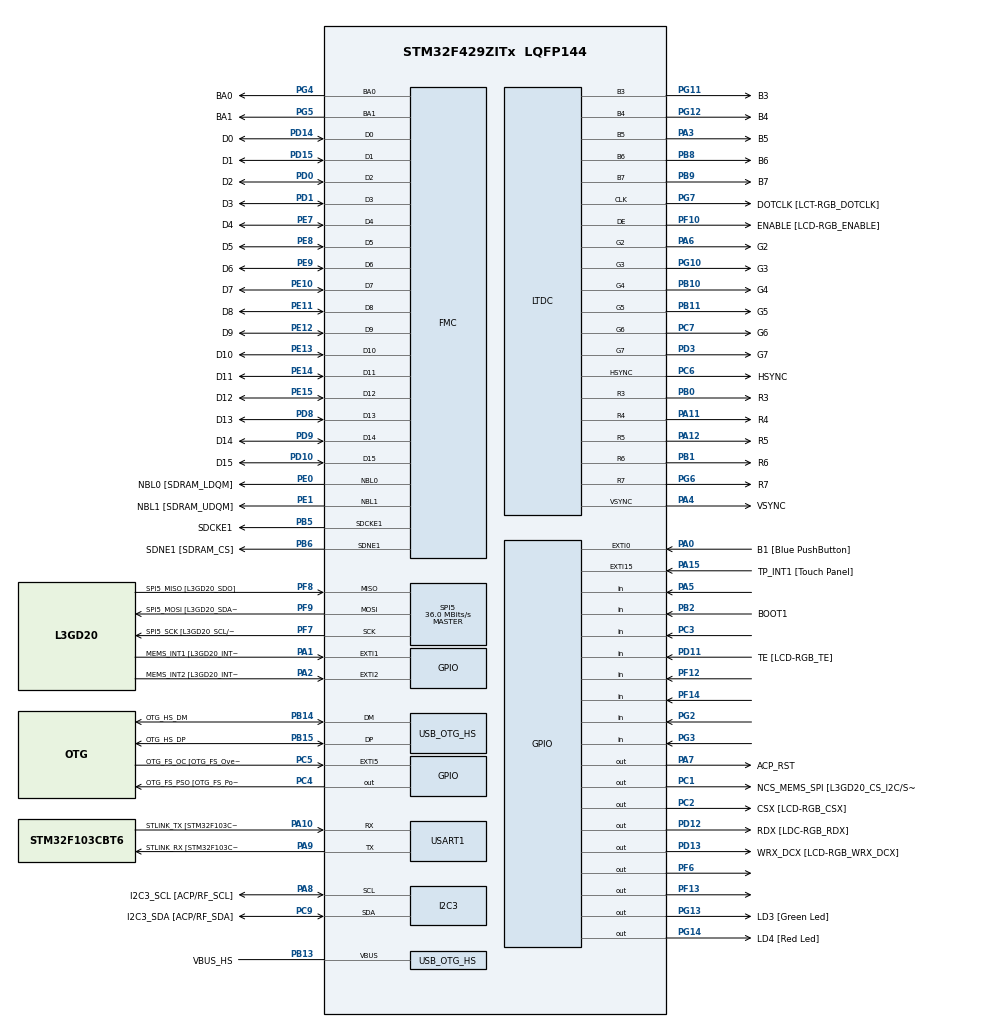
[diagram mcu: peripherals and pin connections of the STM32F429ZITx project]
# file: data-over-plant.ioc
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LTDC.ActiveH=320
LTDC.ActiveW=240
LTDC.Alpha_L0=255
LTDC.BlendingFactor1_L0=LTDC_BLENDING_FACTOR1_PAxCA
LTDC.BlendingFactor2_L0=LTDC_BLENDING_FACTOR2_PAxCA
LTDC.FBStartAdress_L0=0xD0000000
LTDC.HBP=20
LTDC.HFP=10
LTDC.HSync=10
LTDC.ImageHeight_L0=320
LTDC.ImageWidth_L0=240
LTDC.Layers=0
LTDC.PixelFormat_L0=LTDC_PIXEL_FORMAT_RGB565
LTDC.VFP=4
LTDC.VSync=2
LTDC.WindowX1_L0=240
LTDC.WindowY1_L0=320
Mcu.Family=STM32F4
Mcu.Name=STM32F429ZITx
Mcu.Package=LQFP144
NVIC.DMA2D_IRQn=true\:5\:0\:true\:false\:true\:true\:true\:true
NVIC.LTDC_IRQn=true\:5\:0\:true\:false\:true\:true\:true\:true
NVIC.OTG_HS_IRQn=true\:0\:0\:false\:false\:true\:true\:true\:true
NVIC.PriorityGroup=NVIC_PRIORITYGROUP_4
NVIC.TIM6_DAC_IRQn=true\:15\:0\:false\:false\:true\:false\:true\:true
NVIC.TimeBase=TIM6_DAC_IRQn
NVIC.TimeBaseIP=TIM6
PA0/WKUP.GPIO_Label=B1 [Blue PushButton]
PA0/WKUP.GPIO_ModeDefaultEXTI=GPIO_MODE_EVT_RISING
PA0/WKUP.GPIO_PuPd=GPIO_NOPULL
PA0/WKUP.Signal=GPXTI0
PA1.GPIO_Label=MEMS_INT1 [L3GD20_INT1]
PA1.GPIO_ModeDefaultEXTI=GPIO_MODE_EVT_RISING
PA1.GPIO_PuPd=GPIO_NOPULL
PA1.Signal=GPXTI1
PA10.GPIO_Label=STLINK_TX [STM32F103CBT6_PA2]
PA10.Mode=Asynchronous
PA10.Signal=USART1_RX
PA11.GPIO_Label=R4
PA11.GPIO_Mode=GPIO_MODE_AF_PP
PA11.GPIO_PuPd=GPIO_NOPULL
PA11.GPIO_Speed=GPIO_SPEED_FREQ_LOW
PA11.Mode=RGB565
PA11.Signal=LTDC_R4
PA12.GPIO_Label=R5
PA12.GPIO_Mode=GPIO_MODE_AF_PP
PA12.GPIO_PuPd=GPIO_NOPULL
PA12.GPIO_Speed=GPIO_SPEED_FREQ_LOW
PA12.Mode=RGB565
PA12.Signal=LTDC_R5
PA13.GPIO_Label=SWDIO
PA13.Mode=Serial_Wire
PA13.Signal=SYS_JTMS-SWDIO
PA14.GPIO_Label=SWCLK
PA14.Mode=Serial_Wire
PA14.Signal=SYS_JTCK-SWCLK
PA15.GPIO_Label=TP_INT1 [Touch Panel]
PA15.GPIO_ModeDefaultEXTI=GPIO_MODE_EVT_RISING
PA15.GPIO_PuPd=GPIO_NOPULL
PA15.Signal=GPXTI15
PA2.GPIO_Label=MEMS_INT2 [L3GD20_INT2]
PA2.GPIO_ModeDefaultEXTI=GPIO_MODE_EVT_RISING
PA2.GPIO_PuPd=GPIO_NOPULL
PA2.Signal=GPXTI2
PA3.GPIO_Label=B5
PA3.GPIO_Mode=GPIO_MODE_AF_PP
PA3.GPIO_PuPd=GPIO_NOPULL
PA3.GPIO_Speed=GPIO_SPEED_FREQ_LOW
PA3.Mode=RGB565
PA3.Signal=LTDC_B5
PA4.GPIO_Label=VSYNC
PA4.GPIO_Mode=GPIO_MODE_AF_PP
PA4.GPIO_PuPd=GPIO_NOPULL
PA4.GPIO_Speed=GPIO_SPEED_FREQ_LOW
PA4.Mode=RGB565
PA4.Signal=LTDC_VSYNC
PA5.Signal=GPIO_Input
PA6.GPIO_Label=G2
PA6.GPIO_Mode=GPIO_MODE_AF_PP
PA6.GPIO_PuPd=GPIO_NOPULL
PA6.GPIO_Speed=GPIO_SPEED_FREQ_LOW
PA6.Mode=RGB565
PA6.Signal=LTDC_G2
PA7.GPIO_Label=ACP_RST
PA7.GPIO_Mode=GPIO_MODE_OUTPUT_PP
PA7.GPIO_PuPd=GPIO_NOPULL
PA7.GPIO_Speed=GPIO_SPEED_FREQ_LOW
PA7.Signal=GPIO_Output
PA8.GPIO_Label=I2C3_SCL [ACP/RF_SCL]
PA8.GPIO_Mode=GPIO_MODE_AF_OD
PA8.GPIO_Pu=GPIO_PULLUP
PA8.GPIO_PuPd=GPIO_NOPULL
PA8.GPIO_Speed=GPIO_SPEED_FREQ_LOW
PA8.Mode=I2C
PA8.Signal=I2C3_SCL
PA9.GPIO_Label=STLINK_RX [STM32F103CBT6_PA3]
PA9.Mode=Asynchronous
PA9.Signal=USART1_TX
PB0.GPIO_Label=R3
PB0.GPIO_Mode=GPIO_MODE_AF_PP
PB0.GPIO_PuPd=GPIO_NOPULL
PB0.GPIO_Speed=GPIO_SPEED_FREQ_LOW
PB0.Mode=RGB565
PB0.Signal=LTDC_R3
PB1.GPIO_Label=R6
PB1.GPIO_Mode=GPIO_MODE_AF_PP
PB1.GPIO_PuPd=GPIO_NOPULL
PB1.GPIO_Speed=GPIO_SPEED_FREQ_LOW
PB1.Mode=RGB565
PB1.Signal=LTDC_R6
PB10.GPIO_Label=G4
PB10.GPIO_Mode=GPIO_MODE_AF_PP
PB10.GPIO_PuPd=GPIO_NOPULL
PB10.GPIO_Speed=GPIO_SPEED_FREQ_LOW
PB10.Mode=RGB565
PB10.Signal=LTDC_G4
PB11.GPIO_Label=G5
PB11.GPIO_Mode=GPIO_MODE_AF_PP
PB11.GPIO_PuPd=GPIO_NOPULL
PB11.GPIO_Speed=GPIO_SPEED_FREQ_LOW
PB11.Mode=RGB565
PB11.Signal=LTDC_G5
PB12.GPIO_Label=OTG_HS_ID
PB12.GPIO_Mode=GPIO_MODE_AF_PP
PB12.GPIO_PuPd=GPIO_NOPULL
PB12.GPIO_Speed=GPIO_SPEED_FREQ_LOW
PB12.Signal=USB_OTG_HS_ID
PB13.GPIO_Label=VBUS_HS
PB13.GPIO_Mode=GPIO_MODE_INPUT
PB13.GPIO_PuPd=GPIO_NOPULL
PB13.Mode=Activate_VBUS_FS
PB13.Signal=USB_OTG_HS_VBUS
PB14.GPIO_Label=OTG_HS_DM
PB14.GPIO_Mode=GPIO_MODE_AF_PP
PB14.GPIO_PuPd=GPIO_NOPULL
PB14.GPIO_Speed=GPIO_SPEED_FREQ_LOW
PB14.Mode=Host_FS
PB14.Signal=USB_OTG_HS_DM
PB15.GPIO_Label=OTG_HS_DP
PB15.GPIO_Mode=GPIO_MODE_AF_PP
PB15.GPIO_PuPd=GPIO_NOPULL
PB15.GPIO_Speed=GPIO_SPEED_FREQ_LOW
PB15.Mode=Host_FS
PB15.Signal=USB_OTG_HS_DP
PB2/BOOT1.GPIO_Label=BOOT1
PB2/BOOT1.GPIO_Mode=GPIO_MODE_INPUT
PB2/BOOT1.GPIO_PuPd=GPIO_NOPULL
PB2/BOOT1.Signal=GPIO_Input
PB5.GPIO_Label=SDCKE1
PB5.GPIO_Mode=GPIO_MODE_AF_PP
PB5.GPIO_PuPd=GPIO_NOPULL
PB5.GPIO_Speed=GPIO_SPEED_FREQ_VERY_HIGH
PB5.Mode=SdramChipSelect2_1
PB5.Signal=FMC_SDCKE1
PB6.GPIO_Label=SDNE1 [SDRAM_CS]
PB6.GPIO_Mode=GPIO_MODE_AF_PP
PB6.GPIO_PuPd=GPIO_NOPULL
PB6.GPIO_Speed=GPIO_SPEED_FREQ_VERY_HIGH
PB6.Mode=SdramChipSelect2_1
PB6.Signal=FMC_SDNE1
PB8.GPIO_Label=B6
PB8.GPIO_Mode=GPIO_MODE_AF_PP
PB8.GPIO_PuPd=GPIO_NOPULL
PB8.GPIO_Speed=GPIO_SPEED_FREQ_LOW
PB8.Mode=RGB565
PB8.Signal=LTDC_B6
PB9.GPIO_Label=B7
PB9.GPIO_Mode=GPIO_MODE_AF_PP
PB9.GPIO_PuPd=GPIO_NOPULL
PB9.GPIO_Speed=GPIO_SPEED_FREQ_LOW
PB9.Mode=RGB565
PB9.Signal=LTDC_B7
PC0.GPIO_Label=SDNWE
PC0.GPIO_Mode=GPIO_MODE_AF_PP
PC0.GPIO_PuPd=GPIO_NOPULL
PC0.GPIO_Speed=GPIO_SPEED_FREQ_VERY_HIGH
PC0.Signal=FMC_SDNWE
PC1.GPIO_Label=NCS_MEMS_SPI [L3GD20_CS_I2C/SPI]
PC1.GPIO_Mode=GPIO_MODE_OUTPUT_PP
PC1.GPIO_PuPd=GPIO_NOPULL
PC1.GPIO_Speed=GPIO_SPEED_FREQ_LOW
PC1.Signal=GPIO_Output
PC10.GPIO_Label=R2
PC10.GPIO_Mode=GPIO_MODE_AF_PP
PC10.GPIO_PuPd=GPIO_NOPULL
PC10.GPIO_Speed=GPIO_SPEED_FREQ_LOW
PC10.Signal=LTDC_R2
PC14/OSC32_IN.GPIO_Label=PC14-OSC32_IN
PC14/OSC32_IN.Signal=RCC_OSC32_IN
PC15/OSC32_OUT.GPIO_Label=PC15-OSC32_OUT
PC15/OSC32_OUT.Signal=RCC_OSC32_OUT
PC2.GPIO_Label=CSX [LCD-RGB_CSX]
PC2.GPIO_Mode=GPIO_MODE_OUTPUT_PP
PC2.GPIO_PuPd=GPIO_NOPULL
PC2.GPIO_Speed=GPIO_SPEED_FREQ_LOW
PC2.Signal=GPIO_Output
PC3.Signal=GPIO_Input
PC4.GPIO_Label=OTG_FS_PSO [OTG_FS_PowerSwitchOn]
PC4.GPIO_Mode=GPIO_MODE_OUTPUT_PP
PC4.GPIO_PuPd=GPIO_NOPULL
PC4.GPIO_Speed=GPIO_SPEED_FREQ_LOW
PC4.Signal=GPIO_Output
PC5.GPIO_Label=OTG_FS_OC [OTG_FS_OverCurrent]
PC5.GPIO_ModeDefaultEXTI=GPIO_MODE_EVT_RISING
PC5.Signal=GPXTI5
PC6.GPIO_Label=HSYNC
PC6.GPIO_Mode=GPIO_MODE_AF_PP
PC6.GPIO_PuPd=GPIO_NOPULL
PC6.GPIO_Speed=GPIO_SPEED_FREQ_LOW
PC6.Mode=RGB565
PC6.Signal=LTDC_HSYNC
PC7.GPIO_Label=G6
PC7.GPIO_Mode=GPIO_MODE_AF_PP
PC7.GPIO_PuPd=GPIO_NOPULL
PC7.GPIO_Speed=GPIO_SPEED_FREQ_LOW
PC7.Mode=RGB565
PC7.Signal=LTDC_G6
PC9.GPIO_Label=I2C3_SDA [ACP/RF_SDA]
PC9.GPIO_Mode=GPIO_MODE_AF_OD
PC9.GPIO_Pu=GPIO_PULLUP
PC9.GPIO_PuPd=GPIO_NOPULL
PC9.GPIO_Speed=GPIO_SPEED_FREQ_LOW
PC9.Mode=I2C
PC9.Signal=I2C3_SDA
PD0.GPIO_Label=D2
PD0.GPIO_Mode=GPIO_MODE_AF_PP
PD0.GPIO_PuPd=GPIO_NOPULL
PD0.GPIO_Speed=GPIO_SPEED_FREQ_VERY_HIGH
PD0.Signal=FMC_D2_DA2
PD1.GPIO_Label=D3
PD1.GPIO_Mode=GPIO_MODE_AF_PP
PD1.GPIO_PuPd=GPIO_NOPULL
PD1.GPIO_Speed=GPIO_SPEED_FREQ_VERY_HIGH
PD1.Signal=FMC_D3_DA3
PD10.GPIO_Label=D15
PD10.GPIO_Mode=GPIO_MODE_AF_PP
PD10.GPIO_PuPd=GPIO_NOPULL
PD10.GPIO_Speed=GPIO_SPEED_FREQ_VERY_HIGH
PD10.Signal=FMC_D15_DA15
PD11.GPIO_Label=TE [LCD-RGB_TE]
PD11.GPIO_Mode=GPIO_MODE_INPUT
PD11.GPIO_PuPd=GPIO_NOPULL
PD11.Signal=GPIO_Input
PD12.GPIO_Label=RDX [LDC-RGB_RDX]
PD12.GPIO_Mode=GPIO_MODE_OUTPUT_PP
PD12.GPIO_PuPd=GPIO_NOPULL
PD12.GPIO_Speed=GPIO_SPEED_FREQ_LOW
PD12.Signal=GPIO_Output
PD13.GPIO_Label=WRX_DCX [LCD-RGB_WRX_DCX]
PD13.GPIO_Mode=GPIO_MODE_OUTPUT_PP
PD13.GPIO_PuPd=GPIO_NOPULL
PD13.GPIO_Speed=GPIO_SPEED_FREQ_LOW
PD13.Signal=GPIO_Output
PD14.GPIO_Label=D0
PD14.GPIO_Mode=GPIO_MODE_AF_PP
PD14.GPIO_PuPd=GPIO_NOPULL
PD14.GPIO_Speed=GPIO_SPEED_FREQ_VERY_HIGH
PD14.Signal=FMC_D0_DA0
PD15.GPIO_Label=D1
PD15.GPIO_Mode=GPIO_MODE_AF_PP
PD15.GPIO_PuPd=GPIO_NOPULL
PD15.GPIO_Speed=GPIO_SPEED_FREQ_VERY_HIGH
PD15.Signal=FMC_D1_DA1
PD3.GPIO_Label=G7
PD3.GPIO_Mode=GPIO_MODE_AF_PP
PD3.GPIO_PuPd=GPIO_NOPULL
PD3.GPIO_Speed=GPIO_SPEED_FREQ_LOW
PD3.Mode=RGB565
PD3.Signal=LTDC_G7
PD6.GPIO_Label=B2
PD6.GPIO_Mode=GPIO_MODE_AF_PP
PD6.GPIO_PuPd=GPIO_NOPULL
PD6.GPIO_Speed=GPIO_SPEED_FREQ_LOW
PD6.Signal=LTDC_B2
PD8.GPIO_Label=D13
PD8.GPIO_Mode=GPIO_MODE_AF_PP
PD8.GPIO_PuPd=GPIO_NOPULL
PD8.GPIO_Speed=GPIO_SPEED_FREQ_VERY_HIGH
PD8.Signal=FMC_D13_DA13
PD9.GPIO_Label=D14
PD9.GPIO_Mode=GPIO_MODE_AF_PP
PD9.GPIO_PuPd=GPIO_NOPULL
PD9.GPIO_Speed=GPIO_SPEED_FREQ_VERY_HIGH
PD9.Signal=FMC_D14_DA14
PE0.GPIO_Label=NBL0 [SDRAM_LDQM]
PE0.GPIO_Mode=GPIO_MODE_AF_PP
PE0.GPIO_PuPd=GPIO_NOPULL
PE0.GPIO_Speed=GPIO_SPEED_FREQ_VERY_HIGH
PE0.Signal=FMC_NBL0
PE1.GPIO_Label=NBL1 [SDRAM_UDQM]
PE1.GPIO_Mode=GPIO_MODE_AF_PP
PE1.GPIO_PuPd=GPIO_NOPULL
PE1.GPIO_Speed=GPIO_SPEED_FREQ_VERY_HIGH
PE1.Signal=FMC_NBL1
PE10.GPIO_Label=D7
PE10.GPIO_Mode=GPIO_MODE_AF_PP
PE10.GPIO_PuPd=GPIO_NOPULL
PE10.GPIO_Speed=GPIO_SPEED_FREQ_VERY_HIGH
PE10.Signal=FMC_D7_DA7
PE11.GPIO_Label=D8
PE11.GPIO_Mode=GPIO_MODE_AF_PP
PE11.GPIO_PuPd=GPIO_NOPULL
PE11.GPIO_Speed=GPIO_SPEED_FREQ_VERY_HIGH
PE11.Signal=FMC_D8_DA8
PE12.GPIO_Label=D9
PE12.GPIO_Mode=GPIO_MODE_AF_PP
PE12.GPIO_PuPd=GPIO_NOPULL
PE12.GPIO_Speed=GPIO_SPEED_FREQ_VERY_HIGH
PE12.Signal=FMC_D9_DA9
PE13.GPIO_Label=D10
PE13.GPIO_Mode=GPIO_MODE_AF_PP
PE13.GPIO_PuPd=GPIO_NOPULL
PE13.GPIO_Speed=GPIO_SPEED_FREQ_VERY_HIGH
PE13.Signal=FMC_D10_DA10
PE14.GPIO_Label=D11
PE14.GPIO_Mode=GPIO_MODE_AF_PP
PE14.GPIO_PuPd=GPIO_NOPULL
PE14.GPIO_Speed=GPIO_SPEED_FREQ_VERY_HIGH
PE14.Signal=FMC_D11_DA11
PE15.GPIO_Label=D12
PE15.GPIO_Mode=GPIO_MODE_AF_PP
PE15.GPIO_PuPd=GPIO_NOPULL
PE15.GPIO_Speed=GPIO_SPEED_FREQ_VERY_HIGH
PE15.Signal=FMC_D12_DA12
PE7.GPIO_Label=D4
PE7.GPIO_Mode=GPIO_MODE_AF_PP
PE7.GPIO_PuPd=GPIO_NOPULL
PE7.GPIO_Speed=GPIO_SPEED_FREQ_VERY_HIGH
PE7.Signal=FMC_D4_DA4
PE8.GPIO_Label=D5
PE8.GPIO_Mode=GPIO_MODE_AF_PP
PE8.GPIO_PuPd=GPIO_NOPULL
PE8.GPIO_Speed=GPIO_SPEED_FREQ_VERY_HIGH
PE8.Signal=FMC_D5_DA5
PE9.GPIO_Label=D6
PE9.GPIO_Mode=GPIO_MODE_AF_PP
PE9.GPIO_PuPd=GPIO_NOPULL
PE9.GPIO_Speed=GPIO_SPEED_FREQ_VERY_HIGH
PE9.Signal=FMC_D6_DA6
PF0.GPIO_Label=A0
PF0.GPIO_Mode=GPIO_MODE_AF_PP
PF0.GPIO_PuPd=GPIO_NOPULL
PF0.GPIO_Speed=GPIO_SPEED_FREQ_VERY_HIGH
PF0.Signal=FMC_A0
PF1.GPIO_Label=A1
PF1.GPIO_Mode=GPIO_MODE_AF_PP
PF1.GPIO_PuPd=GPIO_NOPULL
PF1.GPIO_Speed=GPIO_SPEED_FREQ_VERY_HIGH
PF1.Signal=FMC_A1
PF10.GPIO_Label=ENABLE [LCD-RGB_ENABLE]
PF10.GPIO_Mode=GPIO_MODE_AF_PP
PF10.GPIO_PuPd=GPIO_NOPULL
PF10.GPIO_Speed=GPIO_SPEED_FREQ_LOW
PF10.Mode=RGB565
PF10.Signal=LTDC_DE
PF11.GPIO_Label=SDNRAS
PF11.GPIO_Mode=GPIO_MODE_AF_PP
PF11.GPIO_PuPd=GPIO_NOPULL
PF11.GPIO_Speed=GPIO_SPEED_FREQ_VERY_HIGH
PF11.Signal=FMC_SDNRAS
PF12.Signal=GPIO_Input
PF13.Signal=GPIO_Output
PF14.Signal=GPIO_Input
PF15.GPIO_Label=A9
PF15.GPIO_Mode=GPIO_MODE_AF_PP
PF15.GPIO_PuPd=GPIO_NOPULL
PF15.GPIO_Speed=GPIO_SPEED_FREQ_VERY_HIGH
PF15.Signal=FMC_A9
PF2.GPIO_Label=A2
PF2.GPIO_Mode=GPIO_MODE_AF_PP
PF2.GPIO_PuPd=GPIO_NOPULL
PF2.GPIO_Speed=GPIO_SPEED_FREQ_VERY_HIGH
PF2.Signal=FMC_A2
PF3.GPIO_Label=A3
PF3.GPIO_Mode=GPIO_MODE_AF_PP
PF3.GPIO_PuPd=GPIO_NOPULL
PF3.GPIO_Speed=GPIO_SPEED_FREQ_VERY_HIGH
PF3.Signal=FMC_A3
PF4.GPIO_Label=A4
PF4.GPIO_Mode=GPIO_MODE_AF_PP
PF4.GPIO_PuPd=GPIO_NOPULL
PF4.GPIO_Speed=GPIO_SPEED_FREQ_VERY_HIGH
PF4.Signal=FMC_A4
PF5.GPIO_Label=A5
PF5.GPIO_Mode=GPIO_MODE_AF_PP
PF5.GPIO_PuPd=GPIO_NOPULL
PF5.GPIO_Speed=GPIO_SPEED_FREQ_VERY_HIGH
PF5.Signal=FMC_A5
PF6.Signal=GPIO_Output
PF7.GPIO_Label=SPI5_SCK [L3GD20_SCL/SPC]
PF7.GPIO_Mode=GPIO_MODE_AF_PP
PF7.GPIO_PuPd=GPIO_NOPULL
PF7.GPIO_Speed=GPIO_SPEED_FREQ_LOW
PF7.Mode=Full_Duplex_Master
PF7.Signal=SPI5_SCK
PF8.GPIO_Label=SPI5_MISO [L3GD20_SDO]
PF8.GPIO_Mode=GPIO_MODE_AF_PP
PF8.GPIO_PuPd=GPIO_NOPULL
PF8.GPIO_Speed=GPIO_SPEED_FREQ_LOW
PF8.Mode=Full_Duplex_Master
PF8.Signal=SPI5_MISO
PF9.GPIO_Label=SPI5_MOSI [L3GD20_SDA/SDI/SDO]
PF9.GPIO_Mode=GPIO_MODE_AF_PP
PF9.GPIO_PuPd=GPIO_NOPULL
PF9.GPIO_Speed=GPIO_SPEED_FREQ_LOW
PF9.Mode=Full_Duplex_Master
PF9.Signal=SPI5_MOSI
PG0.GPIO_Label=A10
PG0.GPIO_Mode=GPIO_MODE_AF_PP
PG0.GPIO_PuPd=GPIO_NOPULL
PG0.GPIO_Speed=GPIO_SPEED_FREQ_VERY_HIGH
PG0.Signal=FMC_A10
PG1.GPIO_Label=A11
PG1.GPIO_Mode=GPIO_MODE_AF_PP
PG1.GPIO_PuPd=GPIO_NOPULL
PG1.GPIO_Speed=GPIO_SPEED_FREQ_VERY_HIGH
PG1.Signal=FMC_A11
PG10.GPIO_Label=G3
PG10.GPIO_Mode=GPIO_MODE_AF_PP
PG10.GPIO_PuPd=GPIO_NOPULL
PG10.GPIO_Speed=GPIO_SPEED_FREQ_LOW
PG10.Mode=RGB565
PG10.Signal=LTDC_G3
PG11.GPIO_Label=B3
PG11.GPIO_Mode=GPIO_MODE_AF_PP
PG11.GPIO_PuPd=GPIO_NOPULL
PG11.GPIO_Speed=GPIO_SPEED_FREQ_LOW
PG11.Mode=RGB565
PG11.Signal=LTDC_B3
PG12.GPIO_Label=B4
PG12.GPIO_Mode=GPIO_MODE_AF_PP
PG12.GPIO_PuPd=GPIO_NOPULL
PG12.GPIO_Speed=GPIO_SPEED_FREQ_LOW
PG12.Mode=RGB565
PG12.Signal=LTDC_B4
PG13.GPIO_Label=LD3 [Green Led]
PG13.GPIO_Mode=GPIO_MODE_OUTPUT_PP
PG13.GPIO_PuPd=GPIO_NOPULL
PG13.GPIO_Speed=GPIO_SPEED_FREQ_LOW
PG13.Signal=GPIO_Output
PG14.GPIO_Label=LD4 [Red Led]
PG14.GPIO_Mode=GPIO_MODE_OUTPUT_PP
PG14.GPIO_PuPd=GPIO_NOPULL
PG14.GPIO_Speed=GPIO_SPEED_FREQ_LOW
PG14.Signal=GPIO_Output
PG15.GPIO_Label=SDNCAS
PG15.GPIO_Mode=GPIO_MODE_AF_PP
PG15.GPIO_PuPd=GPIO_NOPULL
PG15.GPIO_Speed=GPIO_SPEED_FREQ_VERY_HIGH
PG15.Signal=FMC_SDNCAS
PG2.Signal=GPIO_Input
PG3.Signal=GPIO_Input
PG4.GPIO_Label=BA0
PG4.GPIO_Mode=GPIO_MODE_AF_PP
PG4.GPIO_PuPd=GPIO_NOPULL
PG4.GPIO_Speed=GPIO_SPEED_FREQ_VERY_HIGH
PG4.Signal=FMC_A14_BA0
PG5.GPIO_Label=BA1
PG5.GPIO_Mode=GPIO_MODE_AF_PP
PG5.GPIO_PuPd=GPIO_NOPULL
PG5.GPIO_Speed=GPIO_SPEED_FREQ_VERY_HIGH
PG5.Signal=FMC_A15_BA1
PG6.GPIO_Label=R7
PG6.GPIO_Mode=GPIO_MODE_AF_PP
PG6.GPIO_PuPd=GPIO_NOPULL
PG6.GPIO_Speed=GPIO_SPEED_FREQ_LOW
PG6.Mode=RGB565
PG6.Signal=LTDC_R7
PG7.GPIO_Label=DOTCLK [LCT-RGB_DOTCLK]
PG7.GPIO_Mode=GPIO_MODE_AF_PP
PG7.GPIO_PuPd=GPIO_NOPULL
PG7.GPIO_Speed=GPIO_SPEED_FREQ_LOW
PG7.Mode=RGB565
PG7.Signal=LTDC_CLK
PG8.GPIO_Label=SDCLK
PG8.GPIO_Mode=GPIO_MODE_AF_PP
PG8.GPIO_PuPd=GPIO_NOPULL
PG8.GPIO_Speed=GPIO_SPEED_FREQ_VERY_HIGH
PG8.Signal=FMC_SDCLK
PH0/OSC_IN.GPIO_Label=PH0-OSC_IN
PH0/OSC_IN.Mode=HSE-External-Oscillator
PH0/OSC_IN.Signal=RCC_OSC_IN
PH1/OSC_OUT.GPIO_Label=PH1-OSC_OUT
PH1/OSC_OUT.Mode=HSE-External-Oscillator
PH1/OSC_OUT.Signal=RCC_OSC_OUT
ProjectManager.HeapSize=0x200
ProjectManager.StackSize=0x400
ProjectManager.TargetToolchain=STM32CubeIDE
RCC.48MHZClocksFreq_Value=48000000
RCC.AHBFreq_Value=72000000
RCC.APB1CLKDivider=RCC_HCLK_DIV2
RCC.APB1Freq_Value=36000000
RCC.APB1TimFreq_Value=72000000
RCC.APB2Freq_Value=72000000
RCC.APB2TimFreq_Value=72000000
RCC.CortexFreq_Value=72000000
RCC.HCLKFreq_Value=72000000
RCC.HSE_VALUE=8000000
RCC.HSI_VALUE=16000000
RCC.LSE_VALUE=32768
RCC.PLLM=4
RCC.PLLN=72
RCC.PLLQ=3
RCC.PLLSAIN=50
RCC.SYSCLKFreq_VALUE=72000000
RCC.SYSCLKSource=RCC_SYSCLKSOURCE_PLLCLK
RCC.VCOOutputFreq_Value=144000000
SH.FMC_A0.0=FMC_A0
SH.FMC_A1.0=FMC_A1
SH.FMC_A10.0=FMC_A10
SH.FMC_A11.0=FMC_A11
SH.FMC_A14_BA0.0=FMC_BA0,FourSdramBanks1
SH.FMC_A15_BA1.0=FMC_BA1,FourSdramBanks1
SH.FMC_A2.0=FMC_A2
SH.FMC_A3.0=FMC_A3
SH.FMC_A4.0=FMC_A4
SH.FMC_A5.0=FMC_A5
SH.FMC_A9.0=FMC_A9
SH.FMC_D0_DA0.0=FMC_D0,sd-16b-d1
SH.FMC_D10_DA10.0=FMC_D10,sd-16b-d1
SH.FMC_D11_DA11.0=FMC_D11,sd-16b-d1
SH.FMC_D12_DA12.0=FMC_D12,sd-16b-d1
SH.FMC_D13_DA13.0=FMC_D13,sd-16b-d1
SH.FMC_D14_DA14.0=FMC_D14,sd-16b-d1
SH.FMC_D15_DA15.0=FMC_D15,sd-16b-d1
SH.FMC_D1_DA1.0=FMC_D1,sd-16b-d1
SH.FMC_D2_DA2.0=FMC_D2,sd-16b-d1
SH.FMC_D3_DA3.0=FMC_D3,sd-16b-d1
SH.FMC_D4_DA4.0=FMC_D4,sd-16b-d1
SH.FMC_D5_DA5.0=FMC_D5,sd-16b-d1
SH.FMC_D6_DA6.0=FMC_D6,sd-16b-d1
SH.FMC_D7_DA7.0=FMC_D7,sd-16b-d1
SH.FMC_D8_DA8.0=FMC_D8,sd-16b-d1
SH.FMC_D9_DA9.0=FMC_D9,sd-16b-d1
SH.FMC_NBL0.0=FMC_NBL0,Sd2ByteEnable1
SH.FMC_NBL1.0=FMC_NBL1,Sd2ByteEnable1
SH.FMC_SDCLK.0=FMC_SDCLK
SH.FMC_SDNCAS.0=FMC_SDNCAS
SH.FMC_SDNRAS.0=FMC_SDNRAS
SH.FMC_SDNWE.0=FMC_SDNWE
SPI5.CLKPolarity=SPI_POLARITY_LOW
SPI5.CalculateBaudRate=36.0 MBits/s
SPI5.Direction=SPI_DIRECTION_2LINES
SPI5.Mode=SPI_MODE_MASTER
SPI5.VirtualType=VM_MASTER
USART1.VirtualMode=VM_ASYNC
USB_OTG_HS.VirtualMode-Host_FS=Host_FS
VP_CRC_VS_CRC.Mode=CRC_Activate
VP_DMA2D_VS_DMA2D.Mode=DMA2D_Activate
VP_SYS_VS_tim6.Mode=TIM6
VP_TIM1_VS_ClockSourceINT.Mode=Internal
board=STM32F429I-DISC1

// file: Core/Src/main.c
/* USER CODE BEGIN Header */
/**
  ******************************************************************************
  * @file           : main.c
  * @brief          : Main program body
  ******************************************************************************
  * @attention
  *
  * Copyright (c) 2025 STMicroelectronics.
  * All rights reserved.
  *
  * This software is licensed under terms that can be found in the LICENSE file
  * in the root directory of this software component.
  * If no LICENSE file comes with this software, it is provided AS-IS.
  *
  ******************************************************************************
  */
/* USER CODE END Header */
#include "main.h"

/* USER CODE BEGIN Includes */
#include "../../../Drivers/BSP/STM32F429I-Discovery/stm32f429i_discovery.h"
#include "../../../Drivers/BSP/STM32F429I-Discovery/stm32f429i_discovery_lcd.h"
/* USER CODE END Includes */

/* USER CODE BEGIN PD */
//#define TRANSMITTER
//#define RECEIVER
#define LORA_NSS_GPIO_Port GPIOF
#define LORA_NSS_Pin       GPIO_PIN_6
#define LORA_RST_GPIO_Port GPIOF
#define LORA_RST_Pin       GPIO_PIN_13
#define LORA_DIO3 PC3
#define LORA_DIO5 PA5
#define LORA_DIO4 PG2
#define LORA_DIO1 PG3

#define LCD_FRAME_BUFFER_LAYER0                  (LCD_FRAME_BUFFER+0x130000)
#define LCD_FRAME_BUFFER_LAYER1                  LCD_FRAME_BUFFER
#define CONVERTED_FRAME_BUFFER                   (LCD_FRAME_BUFFER+0x260000)
//#define RECEIVER
/* USER CODE END PD */

CRC_HandleTypeDef hcrc;

DMA2D_HandleTypeDef hdma2d;

I2C_HandleTypeDef hi2c3;

LTDC_HandleTypeDef hltdc;

SPI_HandleTypeDef hspi5;

TIM_HandleTypeDef htim1;

UART_HandleTypeDef huart1;

HCD_HandleTypeDef hhcd_USB_OTG_HS;

SDRAM_HandleTypeDef hsdram1;

/* USER CODE BEGIN PV */
uint8_t TX_Buffer [] = "EDOUARD" ;
uint8_t RX_Buffer [1] ; // DATA to receive
/* USER CODE END PV */

void SystemClock_Config(void);
static void MX_GPIO_Init(void);
static void MX_CRC_Init(void);
static void MX_DMA2D_Init(void);
static void MX_I2C3_Init(void);
static void MX_LTDC_Init(void);
static void MX_SPI5_Init(void);
static void MX_TIM1_Init(void);
static void MX_USART1_UART_Init(void);
static void MX_USB_OTG_HS_HCD_Init(void);
static void MX_FMC_Init(void);

/* USER CODE BEGIN 0 */
typedef enum {
	false,
	true
} bool;

void serial_print(char* str)
{
	HAL_UART_Transmit(&huart1, (uint8_t *)str, strlen(str), HAL_MAX_DELAY);
}

void write_register(uint8_t addr, uint8_t value)
{
    uint8_t data[2];
    data[0] = addr | 0x80; // bit 7 à 1 pour écriture
    data[1] = value;

    HAL_GPIO_WritePin(LORA_NSS_GPIO_Port, LORA_NSS_Pin, GPIO_PIN_RESET); // NSS low
    HAL_SPI_Transmit(&hspi5, data, 2, HAL_MAX_DELAY);
    HAL_GPIO_WritePin(LORA_NSS_GPIO_Port, LORA_NSS_Pin, GPIO_PIN_SET);   // NSS high
}

uint8_t read_register(uint8_t addr)
{
    uint8_t value = 0;
    uint8_t reg_addr = addr & 0x7F; // bit 7 à 0 pour lecture (mask pour s'assurer que le bit 7 est à 0)

    HAL_GPIO_WritePin(LORA_NSS_GPIO_Port, LORA_NSS_Pin, GPIO_PIN_RESET); // NSS low
    HAL_SPI_Transmit(&hspi5, &reg_addr, 1, HAL_MAX_DELAY); // Envoyer l'adresse du registre
    HAL_SPI_Receive(&hspi5, &value, 1, HAL_MAX_DELAY);     // Lire la valeur du registre
    HAL_GPIO_WritePin(LORA_NSS_GPIO_Port, LORA_NSS_Pin, GPIO_PIN_SET);   // NSS high

    return value;
}

void init_lora_transmitter(void)
{
	// Mettre en veille (obligatoire avant les changements de mode)
	write_register(0x01, 0x80); // Sleep mode + LoRa

	// Choisir fréquence (ici pour 868 MHz)
	write_register(0x06, 0xD9); // RegFrfMsb = 868 MHz
	write_register(0x07, 0x06);
	write_register(0x08, 0x66);

	// Puissance d’émission (PA_BOOST, 17 dBm)
	//write_register(0x09, 0x8F); // RegPaConfig
	write_register(0x09, 0x80); // RegPaConfig: PA_SELECT=1 (PA_BOOST), OutputPower=0 (minimum)

	// Paramètres LoRa (BW=125 kHz, CR=4/5, SF=7)
	write_register(0x1D, 0x72); // RegModemConfig1: BW=125kHz, CR=4/5, explicit header
	write_register(0x1E, 0x74); // RegModemConfig2: SF=7, CRC On
	write_register(0x26, 0x04); // RegModemConfig3: LowDataRateOptimize=OFF

	// Configuration de la FIFO
	write_register(0x0E, 0x80); // RegFifoTxBaseAddr
	write_register(0x0D, 0x80); // RegFifoAddrPtr
	unsigned char size = 7;
	write_register(0x22, size); // RegPayloadLength (taille du message)

	// Écriture des données dans le FIFO
	for (int i = 0; i < size; i++) {
	  write_register(0x00, TX_Buffer[i]); // RegFifo
	}

	// Passage en mode émetteur
	write_register(0x01, 0x83); // TX mode + LoRa
}

void init_lora(void)
{
#ifdef TRANSMITTER
	init_lora_transmitter();
#endif
#ifdef RECEIVER
	init_lora_receiver();
#endif
}

void lora_reset(void)
{
    HAL_GPIO_WritePin(LORA_RST_GPIO_Port, LORA_RST_Pin, GPIO_PIN_RESET);
    HAL_Delay(10); // maintenir RESET à 0 pendant 10ms
    HAL_GPIO_WritePin(LORA_RST_GPIO_Port, LORA_RST_Pin, GPIO_PIN_SET);
    HAL_Delay(10); // attendre encore un peu après le relâchement
}

uint8_t lora_version(void)
{
	uint8_t version = read_register(0x42);

	char buf[32];
	snprintf(buf, sizeof(buf), "RegVersion = 0x%02X\r\n", version);
	serial_print(buf);

	if (version == 0x12) {
		serial_print("RFM95 détecté\r\n");
	} else {
		serial_print("Erreur RFM95 !\r\n");
	}

	return version;
}

uint8_t lora_status(void)
{
    return read_register(0x12); // RegIrqFlags
}

void lora_clear_irq(void)
{
    write_register(0x12, 0xFF); // Effacer tous les drapeaux d'interruption
}

char lora_is_tx_done(void)
{
    return (lora_status() & 0x08) != 0; // Vérifie le drapeau TxDone
}

void send_lora_packet(const uint8_t* data, uint8_t size)
{
    // Mettre en mode veille
    write_register(0x01, 0x81);  // Standby mode + LoRa

    // Configurer le pointeur FIFO pour l'écriture
    write_register(0x0D, 0x80);  // RegFifoAddrPtr

    // Écrire les données dans la FIFO
    for (int i = 0; i < size; i++) {
        write_register(0x00, data[i]);  // RegFifo
    }

    // Définir la taille des données
    write_register(0x22, size);  // RegPayloadLength

    // Démarrer la transmission
    write_register(0x01, 0x83);  // TX mode + LoRa
}

// Structure pour stocker les informations de paquet reçu
typedef struct {
    uint8_t buffer[256];  // Buffer pour stocker les données reçues
    uint8_t size;         // Taille des données reçues
    int8_t rssi;          // Force du signal
    float snr;            // Rapport signal/bruit
} LoRaPacket_t;

// Fonction pour initialiser le mode récepteur
void init_lora_receiver(void)
{
    // Mettre en veille (obligatoire avant les changements de mode)
    write_register(0x01, 0x80); // Sleep mode + LoRa

    // Choisir fréquence (ici pour 868 MHz - même fréquence que l'émetteur)
    write_register(0x06, 0xD9); // RegFrfMsb = 868 MHz
    write_register(0x07, 0x06);
    write_register(0x08, 0x66);

    // Paramètres LoRa (BW=125 kHz, CR=4/5, SF=7) - comme l'émetteur
    write_register(0x1D, 0x72); // RegModemConfig1: BW=125kHz, CR=4/5, explicit header
    write_register(0x1E, 0x74); // RegModemConfig2: SF=7, CRC On
    write_register(0x26, 0x04); // RegModemConfig3: LowDataRateOptimize=OFF

    // Optimisation pour la réception
    write_register(0x0F, 0x00); // RegFifoRxBaseAddr - adresse de base pour le buffer de réception

    // Configurer LNA (Low Noise Amplifier) pour la réception
    write_register(0x0C, 0x23); // RegLna: gain élevé, boost On

    // Configurer la détection de préambule
    write_register(0x1F, 0x08); // RegPreambleDetect: 1 octet de préambule requis

    // Régler le seuil de détection pour optimiser la sensibilité
    write_register(0x20, 0x00); // RegDetectionThreshold: valeur par défaut

    // Effacer tous les drapeaux d'interruption
    write_register(0x12, 0xFF);

    // Activer les interruptions RxDone et PayloadCrcError
    write_register(0x11, 0x00); // RegIrqFlags: désactiver toutes les interruptions

    // Passer en mode réception continue
    write_register(0x01, 0x85); // RX continuous mode + LoRa

    serial_print("Module LoRa initialisé en mode réception\r\n");
}

// Vérifier si un paquet est disponible
bool lora_is_packet_available(void)
{
    uint8_t irq_flags = read_register(0x12); // RegIrqFlags
    return (irq_flags & 0x40) != 0; // RxDone flag
}

// Vérifier si la réception contient une erreur CRC
bool lora_has_crc_error(void)
{
    uint8_t irq_flags = read_register(0x12); // RegIrqFlags
    return (irq_flags & 0x20) != 0; // PayloadCrcError flag
}

// Lire un paquet complet avec informations supplémentaires
LoRaPacket_t lora_receive_packet(void)
{
    LoRaPacket_t packet = {0};

    // Vérifier si un paquet est disponible et pas d'erreur CRC
    if (lora_is_packet_available() && !lora_has_crc_error()) {
        // Récupérer les informations de qualité du signal
        packet.rssi = -137 + read_register(0x1A); // RegRssiValue (en dBm)

        // Convertir la valeur SNR lue (complément à 2 sur 8 bits)
        int8_t raw_snr = (int8_t)read_register(0x19); // RegPktSnrValue
        packet.snr = raw_snr * 0.25f; // Convertir en dB

        // Récupérer la taille du paquet
        packet.size = read_register(0x13); // RegRxNbBytes

        // Lire l'adresse du dernier octet dans la FIFO
        uint8_t current_addr = read_register(0x10); // RegFifoRxCurrentAddr

        // Positionner le pointeur de FIFO à l'adresse du début de la réception
        write_register(0x0D, current_addr); // RegFifoAddrPtr

        // Lire les données
        for (uint8_t i = 0; i < packet.size && i < sizeof(packet.buffer); i++) {
            packet.buffer[i] = read_register(0x00); // RegFifo
        }

        // Afficher les informations de réception
        char buf[128];
        snprintf(buf, sizeof(buf), "Paquet reçu (%d octets), RSSI: %d dBm, SNR: %.2f dB\r\n", packet.size, packet.rssi, packet.snr);
        serial_print(buf);

        // Afficher le contenu du paquet (en ASCII)
        serial_print("Contenu: ");
        for (uint8_t i = 0; i < packet.size && i < sizeof(packet.buffer); i++) {
            char c = packet.buffer[i];
            if (c >= 32 && c <= 126) {  // Si c'est un caractère imprimable
                char ch[2] = {c, 0};
                serial_print(ch);
            } else {
                serial_print(".");  // Caractère non imprimable
            }
        }
        serial_print("\r\n");

        // Effacer le drapeau RxDone
        write_register(0x12, 0x40);
    }

    return packet;
}

void config_lcd()
{
	  BSP_LCD_Init();

	  /* Layer2 Init */
	  BSP_LCD_LayerDefaultInit(1, LCD_FRAME_BUFFER_LAYER1);
	  /* Set Foreground Layer */
	  BSP_LCD_SelectLayer(1);
	  /* Clear the LCD */
	  BSP_LCD_Clear(LCD_COLOR_WHITE);
	  BSP_LCD_SetColorKeying(1, LCD_COLOR_WHITE);
	  BSP_LCD_SetLayerVisible(1, DISABLE);

	  /* Layer1 Init */
	  BSP_LCD_LayerDefaultInit(0, LCD_FRAME_BUFFER_LAYER0);

	  /* Set Foreground Layer */
	  BSP_LCD_SelectLayer(0);

	  /* Enable The LCD */
	  BSP_LCD_DisplayOn();

	  /* Clear the LCD */
	  BSP_LCD_Clear(LCD_COLOR_WHITE);
}
/* USER CODE END 0 */

int main(void)
{

  /* MCU Configuration--------------------------------------------------------*/

  /* Reset of all peripherals, Initializes the Flash interface and the Systick. */
  HAL_Init();

  /* Configure the system clock */
  SystemClock_Config();

  /* Initialize all configured peripherals */
  MX_GPIO_Init();
  MX_CRC_Init();
  MX_DMA2D_Init();
  MX_I2C3_Init();
  MX_LTDC_Init();
  MX_SPI5_Init();
  MX_TIM1_Init();
  MX_USART1_UART_Init();
  MX_USB_OTG_HS_HCD_Init();
  MX_FMC_Init();
  /* USER CODE BEGIN 2 */
  config_lcd();
  BSP_LCD_DisplayStringAt(0, 0, (uint8_t *)"ABCDEFGHIJKLMNOPQRSTUVWXYZ", LEFT_MODE);
#ifdef RECEIVER
    lora_reset();
    HAL_Delay(10);

    uint8_t version = lora_version();
    if (version == 0x12) {
      serial_print("Version correcte, initialisation du récepteur...\r\n");
      init_lora();
    } else {
      serial_print("Version incorrecte, vérifiez le module!\r\n");
    }
#endif

#ifdef TRANSMITTER
  lora_reset();
  HAL_Delay(10);

  uint8_t version = lora_version();
  if (version == 0x12) {
      serial_print("Initialisation du module LoRa...\r\n");

      // Préparation pour la transmission
      init_lora();  // Initialiser le module et envoyer les données

      // Attendre que la transmission soit terminée
      while (!lora_is_tx_done()) {
          HAL_Delay(10);
      }

      serial_print("Transmission terminee!\r\n");

      // Effacer les drapeaux d'interruption
      lora_clear_irq();
  } else {
      serial_print("Module LoRa non detecte ou incompatible\r\n");
  }
#endif

  /* USER CODE END 2 */

  /* Infinite loop */
  while (1)
  {

    /* USER CODE BEGIN 3 */

#ifdef RECEIVER
  // Vérifier si un paquet est disponible
  if (lora_is_packet_available()) {
    // Lire le paquet
    LoRaPacket_t packet = lora_receive_packet();

    // Traiter les données reçues (par exemple, le premier octet peut être un ID)
    if (packet.size > 0) {
      // Exemple: allumez une LED si le premier octet est 'E' (pour 'EDOUARD')
      if (packet.buffer[0] == 'E') {
        HAL_GPIO_WritePin(LD3_GPIO_Port, LD3_Pin, GPIO_PIN_SET);
        HAL_Delay(500);
        HAL_GPIO_WritePin(LD3_GPIO_Port, LD3_Pin, GPIO_PIN_RESET);
      }
    }
  }
  HAL_Delay(10); // Petit délai pour ne pas surcharger le processeur
#endif

#ifdef TRANSMITTER
		uint32_t current_time = HAL_GetTick();

		// Vérifier si le module est prêt (pas en train d'émettre)
		//if (!(read_register(0x01) & 0x07)) {  // Vérifier si le module est en mode veille
		  send_lora_packet(TX_Buffer, sizeof(TX_Buffer) - 1);  // Ignorer le zéro terminal
		  serial_print("Paquet envoye\r\n");
		//}

		// Vérifier si une transmission est terminée
		/*if (lora_is_tx_done()) {
		  serial_print("Transmission terminee\r\n");
		  lora_clear_irq();  // Effacer les drapeaux d'interruption
		}*/
#endif
  }
  /* USER CODE END 3 */
}

void SystemClock_Config(void)
{
  RCC_ClkInitTypeDef RCC_ClkInitStruct;
  RCC_OscInitTypeDef RCC_OscInitStruct;

  /* Enable Power Control clock */
  __HAL_RCC_PWR_CLK_ENABLE();

  /* The voltage scaling allows optimizing the power consumption when the device is
     clocked below the maximum system frequency, to update the voltage scaling value
     regarding system frequency refer to product datasheet.  */
  __HAL_PWR_VOLTAGESCALING_CONFIG(PWR_REGULATOR_VOLTAGE_SCALE1);

  /* Enable HSE Oscillator and activate PLL with HSE as source */
  RCC_OscInitStruct.OscillatorType = RCC_OSCILLATORTYPE_HSE;
  RCC_OscInitStruct.HSEState = RCC_HSE_ON;
  RCC_OscInitStruct.PLL.PLLState = RCC_PLL_ON;
  RCC_OscInitStruct.PLL.PLLSource = RCC_PLLSOURCE_HSE;
  RCC_OscInitStruct.PLL.PLLM = 8;
  RCC_OscInitStruct.PLL.PLLN = 336;
  RCC_OscInitStruct.PLL.PLLP = 2;
  RCC_OscInitStruct.PLL.PLLQ = 7;
  HAL_RCC_OscConfig(&RCC_OscInitStruct);

  /* Select PLL as system clock source and configure the HCLK, PCLK1 and PCLK2
     clocks dividers */
  RCC_ClkInitStruct.ClockType = (RCC_CLOCKTYPE_SYSCLK | RCC_CLOCKTYPE_HCLK | RCC_CLOCKTYPE_PCLK1 | RCC_CLOCKTYPE_PCLK2);
  RCC_ClkInitStruct.SYSCLKSource = RCC_SYSCLKSOURCE_PLLCLK;
  RCC_ClkInitStruct.AHBCLKDivider = RCC_SYSCLK_DIV1;
  RCC_ClkInitStruct.APB1CLKDivider = RCC_HCLK_DIV4;
  RCC_ClkInitStruct.APB2CLKDivider = RCC_HCLK_DIV2;
  HAL_RCC_ClockConfig(&RCC_ClkInitStruct, FLASH_LATENCY_5);
}

static void MX_CRC_Init(void)
{

  hcrc.Instance = CRC;
  if (HAL_CRC_Init(&hcrc) != HAL_OK)
  {
    Error_Handler();
  }

}

static void MX_DMA2D_Init(void)
{

  hdma2d.Instance = DMA2D;
  hdma2d.Init.Mode = DMA2D_M2M;
  hdma2d.Init.ColorMode = DMA2D_OUTPUT_ARGB8888;
  hdma2d.Init.OutputOffset = 0;
  hdma2d.LayerCfg[1].InputOffset = 0;
  hdma2d.LayerCfg[1].InputColorMode = DMA2D_INPUT_ARGB8888;
  hdma2d.LayerCfg[1].AlphaMode = DMA2D_NO_MODIF_ALPHA;
  hdma2d.LayerCfg[1].InputAlpha = 0;
  if (HAL_DMA2D_Init(&hdma2d) != HAL_OK)
  {
    Error_Handler();
  }
  if (HAL_DMA2D_ConfigLayer(&hdma2d, 1) != HAL_OK)
  {
    Error_Handler();
  }

}

static void MX_I2C3_Init(void)
{

  hi2c3.Instance = I2C3;
  hi2c3.Init.ClockSpeed = 100000;
  hi2c3.Init.DutyCycle = I2C_DUTYCYCLE_2;
  hi2c3.Init.OwnAddress1 = 0;
  hi2c3.Init.AddressingMode = I2C_ADDRESSINGMODE_7BIT;
  hi2c3.Init.DualAddressMode = I2C_DUALADDRESS_DISABLE;
  hi2c3.Init.OwnAddress2 = 0;
  hi2c3.Init.GeneralCallMode = I2C_GENERALCALL_DISABLE;
  hi2c3.Init.NoStretchMode = I2C_NOSTRETCH_DISABLE;
  if (HAL_I2C_Init(&hi2c3) != HAL_OK)
  {
    Error_Handler();
  }

  /** Configure Analogue filter
  */
  if (HAL_I2CEx_ConfigAnalogFilter(&hi2c3, I2C_ANALOGFILTER_ENABLE) != HAL_OK)
  {
    Error_Handler();
  }

  /** Configure Digital filter
  */
  if (HAL_I2CEx_ConfigDigitalFilter(&hi2c3, 0) != HAL_OK)
  {
    Error_Handler();
  }

}

static void MX_LTDC_Init(void)
{

  LTDC_LayerCfgTypeDef pLayerCfg = {0};

  hltdc.Instance = LTDC;
  hltdc.Init.HSPolarity = LTDC_HSPOLARITY_AL;
  hltdc.Init.VSPolarity = LTDC_VSPOLARITY_AL;
  hltdc.Init.DEPolarity = LTDC_DEPOLARITY_AL;
  hltdc.Init.PCPolarity = LTDC_PCPOLARITY_IPC;
  hltdc.Init.HorizontalSync = 9;
  hltdc.Init.VerticalSync = 1;
  hltdc.Init.AccumulatedHBP = 29;
  hltdc.Init.AccumulatedVBP = 3;
  hltdc.Init.AccumulatedActiveW = 269;
  hltdc.Init.AccumulatedActiveH = 323;
  hltdc.Init.TotalWidth = 279;
  hltdc.Init.TotalHeigh = 327;
  hltdc.Init.Backcolor.Blue = 0;
  hltdc.Init.Backcolor.Green = 0;
  hltdc.Init.Backcolor.Red = 0;
  if (HAL_LTDC_Init(&hltdc) != HAL_OK)
  {
    Error_Handler();
  }
  pLayerCfg.WindowX0 = 0;
  pLayerCfg.WindowX1 = 240;
  pLayerCfg.WindowY0 = 0;
  pLayerCfg.WindowY1 = 320;
  pLayerCfg.PixelFormat = LTDC_PIXEL_FORMAT_RGB565;
  pLayerCfg.Alpha = 255;
  pLayerCfg.Alpha0 = 0;
  pLayerCfg.BlendingFactor1 = LTDC_BLENDING_FACTOR1_PAxCA;
  pLayerCfg.BlendingFactor2 = LTDC_BLENDING_FACTOR2_PAxCA;
  pLayerCfg.FBStartAdress = 0xD0000000;
  pLayerCfg.ImageWidth = 240;
  pLayerCfg.ImageHeight = 320;
  pLayerCfg.Backcolor.Blue = 0;
  pLayerCfg.Backcolor.Green = 0;
  pLayerCfg.Backcolor.Red = 0;
  if (HAL_LTDC_ConfigLayer(&hltdc, &pLayerCfg, 0) != HAL_OK)
  {
    Error_Handler();
  }

}

static void MX_SPI5_Init(void)
{

  /* SPI5 parameter configuration*/
  hspi5.Instance = SPI5;
  hspi5.Init.Mode = SPI_MODE_MASTER;
  hspi5.Init.Direction = SPI_DIRECTION_2LINES;
  hspi5.Init.DataSize = SPI_DATASIZE_8BIT;
  hspi5.Init.CLKPolarity = SPI_POLARITY_LOW;
  hspi5.Init.CLKPhase = SPI_PHASE_1EDGE;
  hspi5.Init.NSS = SPI_NSS_SOFT;
  hspi5.Init.BaudRatePrescaler = SPI_BAUDRATEPRESCALER_2;
  hspi5.Init.FirstBit = SPI_FIRSTBIT_MSB;
  hspi5.Init.TIMode = SPI_TIMODE_DISABLE;
  hspi5.Init.CRCCalculation = SPI_CRCCALCULATION_DISABLE;
  hspi5.Init.CRCPolynomial = 10;
  if (HAL_SPI_Init(&hspi5) != HAL_OK)
  {
    Error_Handler();
  }

}

static void MX_TIM1_Init(void)
{

  TIM_ClockConfigTypeDef sClockSourceConfig = {0};
  TIM_MasterConfigTypeDef sMasterConfig = {0};

  htim1.Instance = TIM1;
  htim1.Init.Prescaler = 0;
  htim1.Init.CounterMode = TIM_COUNTERMODE_UP;
  htim1.Init.Period = 65535;
  htim1.Init.ClockDivision = TIM_CLOCKDIVISION_DIV1;
  htim1.Init.RepetitionCounter = 0;
  htim1.Init.AutoReloadPreload = TIM_AUTORELOAD_PRELOAD_DISABLE;
  if (HAL_TIM_Base_Init(&htim1) != HAL_OK)
  {
    Error_Handler();
  }
  sClockSourceConfig.ClockSource = TIM_CLOCKSOURCE_INTERNAL;
  if (HAL_TIM_ConfigClockSource(&htim1, &sClockSourceConfig) != HAL_OK)
  {
    Error_Handler();
  }
  sMasterConfig.MasterOutputTrigger = TIM_TRGO_RESET;
  sMasterConfig.MasterSlaveMode = TIM_MASTERSLAVEMODE_DISABLE;
  if (HAL_TIMEx_MasterConfigSynchronization(&htim1, &sMasterConfig) != HAL_OK)
  {
    Error_Handler();
  }

}

static void MX_USART1_UART_Init(void)
{

  huart1.Instance = USART1;
  huart1.Init.BaudRate = 115200;
  huart1.Init.WordLength = UART_WORDLENGTH_8B;
  huart1.Init.StopBits = UART_STOPBITS_1;
  huart1.Init.Parity = UART_PARITY_NONE;
  huart1.Init.Mode = UART_MODE_TX_RX;
  huart1.Init.HwFlowCtl = UART_HWCONTROL_NONE;
  huart1.Init.OverSampling = UART_OVERSAMPLING_16;
  if (HAL_UART_Init(&huart1) != HAL_OK)
  {
    Error_Handler();
  }

}

static void MX_USB_OTG_HS_HCD_Init(void)
{

  hhcd_USB_OTG_HS.Instance = USB_OTG_HS;
  hhcd_USB_OTG_HS.Init.Host_channels = 12;
  hhcd_USB_OTG_HS.Init.speed = HCD_SPEED_FULL;
  hhcd_USB_OTG_HS.Init.dma_enable = DISABLE;
  hhcd_USB_OTG_HS.Init.phy_itface = USB_OTG_EMBEDDED_PHY;
  hhcd_USB_OTG_HS.Init.Sof_enable = DISABLE;
  hhcd_USB_OTG_HS.Init.low_power_enable = DISABLE;
  hhcd_USB_OTG_HS.Init.vbus_sensing_enable = DISABLE;
  hhcd_USB_OTG_HS.Init.use_external_vbus = DISABLE;
  if (HAL_HCD_Init(&hhcd_USB_OTG_HS) != HAL_OK)
  {
    Error_Handler();
  }

}

/* FMC initialization function */
static void MX_FMC_Init(void)
{

  FMC_SDRAM_TimingTypeDef SdramTiming = {0};

  /** Perform the SDRAM1 memory initialization sequence
  */
  hsdram1.Instance = FMC_SDRAM_DEVICE;
  /* hsdram1.Init */
  hsdram1.Init.SDBank = FMC_SDRAM_BANK2;
  hsdram1.Init.ColumnBitsNumber = FMC_SDRAM_COLUMN_BITS_NUM_8;
  hsdram1.Init.RowBitsNumber = FMC_SDRAM_ROW_BITS_NUM_11;
  hsdram1.Init.MemoryDataWidth = FMC_SDRAM_MEM_BUS_WIDTH_16;
  hsdram1.Init.InternalBankNumber = FMC_SDRAM_INTERN_BANKS_NUM_4;
  hsdram1.Init.CASLatency = FMC_SDRAM_CAS_LATENCY_1;
  hsdram1.Init.WriteProtection = FMC_SDRAM_WRITE_PROTECTION_DISABLE;
  hsdram1.Init.SDClockPeriod = FMC_SDRAM_CLOCK_DISABLE;
  hsdram1.Init.ReadBurst = FMC_SDRAM_RBURST_DISABLE;
  hsdram1.Init.ReadPipeDelay = FMC_SDRAM_RPIPE_DELAY_0;
  /* SdramTiming */
  SdramTiming.LoadToActiveDelay = 16;
  SdramTiming.ExitSelfRefreshDelay = 16;
  SdramTiming.SelfRefreshTime = 16;
  SdramTiming.RowCycleDelay = 16;
  SdramTiming.WriteRecoveryTime = 16;
  SdramTiming.RPDelay = 16;
  SdramTiming.RCDDelay = 16;

  if (HAL_SDRAM_Init(&hsdram1, &SdramTiming) != HAL_OK)
  {
    Error_Handler( );
  }

}

static void MX_GPIO_Init(void)
{
  GPIO_InitTypeDef GPIO_InitStruct = {0};

  /* GPIO Ports Clock Enable */
  __HAL_RCC_GPIOC_CLK_ENABLE();
  __HAL_RCC_GPIOF_CLK_ENABLE();
  __HAL_RCC_GPIOH_CLK_ENABLE();
  __HAL_RCC_GPIOA_CLK_ENABLE();
  __HAL_RCC_GPIOB_CLK_ENABLE();
  __HAL_RCC_GPIOG_CLK_ENABLE();
  __HAL_RCC_GPIOE_CLK_ENABLE();
  __HAL_RCC_GPIOD_CLK_ENABLE();

  /*Configure GPIO pin Output Level */
  HAL_GPIO_WritePin(GPIOF, GPIO_PIN_6|GPIO_PIN_13, GPIO_PIN_RESET);

  /*Configure GPIO pin Output Level */
  HAL_GPIO_WritePin(GPIOC, NCS_MEMS_SPI_Pin|CSX_Pin|OTG_FS_PSO_Pin, GPIO_PIN_RESET);

  /*Configure GPIO pin Output Level */
  HAL_GPIO_WritePin(ACP_RST_GPIO_Port, ACP_RST_Pin, GPIO_PIN_RESET);

  /*Configure GPIO pin Output Level */
  HAL_GPIO_WritePin(GPIOD, RDX_Pin|WRX_DCX_Pin, GPIO_PIN_RESET);

  /*Configure GPIO pin Output Level */
  HAL_GPIO_WritePin(GPIOG, LD3_Pin|LD4_Pin, GPIO_PIN_RESET);

  /*Configure GPIO pins : PF6 PF13 */
  GPIO_InitStruct.Pin = GPIO_PIN_6|GPIO_PIN_13;
  GPIO_InitStruct.Mode = GPIO_MODE_OUTPUT_PP;
  GPIO_InitStruct.Pull = GPIO_NOPULL;
  GPIO_InitStruct.Speed = GPIO_SPEED_FREQ_LOW;
  HAL_GPIO_Init(GPIOF, &GPIO_InitStruct);

  /*Configure GPIO pins : NCS_MEMS_SPI_Pin CSX_Pin OTG_FS_PSO_Pin */
  GPIO_InitStruct.Pin = NCS_MEMS_SPI_Pin|CSX_Pin|OTG_FS_PSO_Pin;
  GPIO_InitStruct.Mode = GPIO_MODE_OUTPUT_PP;
  GPIO_InitStruct.Pull = GPIO_NOPULL;
  GPIO_InitStruct.Speed = GPIO_SPEED_FREQ_LOW;
  HAL_GPIO_Init(GPIOC, &GPIO_InitStruct);

  /*Configure GPIO pin : PC3 */
  GPIO_InitStruct.Pin = GPIO_PIN_3;
  GPIO_InitStruct.Mode = GPIO_MODE_INPUT;
  GPIO_InitStruct.Pull = GPIO_NOPULL;
  HAL_GPIO_Init(GPIOC, &GPIO_InitStruct);

  /*Configure GPIO pins : B1_Pin MEMS_INT1_Pin MEMS_INT2_Pin TP_INT1_Pin */
  GPIO_InitStruct.Pin = B1_Pin|MEMS_INT1_Pin|MEMS_INT2_Pin|TP_INT1_Pin;
  GPIO_InitStruct.Mode = GPIO_MODE_EVT_RISING;
  GPIO_InitStruct.Pull = GPIO_NOPULL;
  HAL_GPIO_Init(GPIOA, &GPIO_InitStruct);

  /*Configure GPIO pin : PA5 */
  GPIO_InitStruct.Pin = GPIO_PIN_5;
  GPIO_InitStruct.Mode = GPIO_MODE_INPUT;
  GPIO_InitStruct.Pull = GPIO_NOPULL;
  HAL_GPIO_Init(GPIOA, &GPIO_InitStruct);

  /*Configure GPIO pin : ACP_RST_Pin */
  GPIO_InitStruct.Pin = ACP_RST_Pin;
  GPIO_InitStruct.Mode = GPIO_MODE_OUTPUT_PP;
  GPIO_InitStruct.Pull = GPIO_NOPULL;
  GPIO_InitStruct.Speed = GPIO_SPEED_FREQ_LOW;
  HAL_GPIO_Init(ACP_RST_GPIO_Port, &GPIO_InitStruct);

  /*Configure GPIO pin : OTG_FS_OC_Pin */
  GPIO_InitStruct.Pin = OTG_FS_OC_Pin;
  GPIO_InitStruct.Mode = GPIO_MODE_EVT_RISING;
  GPIO_InitStruct.Pull = GPIO_NOPULL;
  HAL_GPIO_Init(OTG_FS_OC_GPIO_Port, &GPIO_InitStruct);

  /*Configure GPIO pin : BOOT1_Pin */
  GPIO_InitStruct.Pin = BOOT1_Pin;
  GPIO_InitStruct.Mode = GPIO_MODE_INPUT;
  GPIO_InitStruct.Pull = GPIO_NOPULL;
  HAL_GPIO_Init(BOOT1_GPIO_Port, &GPIO_InitStruct);

  /*Configure GPIO pins : PF12 PF14 */
  GPIO_InitStruct.Pin = GPIO_PIN_12|GPIO_PIN_14;
  GPIO_InitStruct.Mode = GPIO_MODE_INPUT;
  GPIO_InitStruct.Pull = GPIO_NOPULL;
  HAL_GPIO_Init(GPIOF, &GPIO_InitStruct);

  /*Configure GPIO pin : TE_Pin */
  GPIO_InitStruct.Pin = TE_Pin;
  GPIO_InitStruct.Mode = GPIO_MODE_INPUT;
  GPIO_InitStruct.Pull = GPIO_NOPULL;
  HAL_GPIO_Init(TE_GPIO_Port, &GPIO_InitStruct);

  /*Configure GPIO pins : RDX_Pin WRX_DCX_Pin */
  GPIO_InitStruct.Pin = RDX_Pin|WRX_DCX_Pin;
  GPIO_InitStruct.Mode = GPIO_MODE_OUTPUT_PP;
  GPIO_InitStruct.Pull = GPIO_NOPULL;
  GPIO_InitStruct.Speed = GPIO_SPEED_FREQ_LOW;
  HAL_GPIO_Init(GPIOD, &GPIO_InitStruct);

  /*Configure GPIO pins : PG2 PG3 */
  GPIO_InitStruct.Pin = GPIO_PIN_2|GPIO_PIN_3;
  GPIO_InitStruct.Mode = GPIO_MODE_INPUT;
  GPIO_InitStruct.Pull = GPIO_NOPULL;
  HAL_GPIO_Init(GPIOG, &GPIO_InitStruct);

  /*Configure GPIO pins : LD3_Pin LD4_Pin */
  GPIO_InitStruct.Pin = LD3_Pin|LD4_Pin;
  GPIO_InitStruct.Mode = GPIO_MODE_OUTPUT_PP;
  GPIO_InitStruct.Pull = GPIO_NOPULL;
  GPIO_InitStruct.Speed = GPIO_SPEED_FREQ_LOW;
  HAL_GPIO_Init(GPIOG, &GPIO_InitStruct);

}

void HAL_TIM_PeriodElapsedCallback(TIM_HandleTypeDef *htim)
{
  if (htim->Instance == TIM6)
  {
    HAL_IncTick();
  }
}

void Error_Handler(void)
{
  __disable_irq();
  while (1)
  {
  }
}
